VERSION 5.8 ;
BUSBITCHARS "[]" ;
DIVIDERCHAR "/" ;
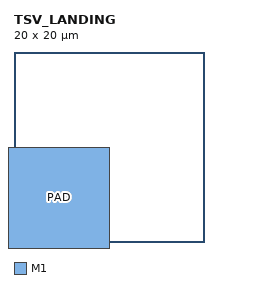
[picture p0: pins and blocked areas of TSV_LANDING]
MACRO TSV_LANDING
 CLASS COVER BUMP ;
 ORIGIN 0 0 ;
 SIZE 20 BY 20 ;
 PIN PAD
  DIRECTION INOUT ;
  USE SIGNAL ;
  PORT
   LAYER M1 ;
   RECT -10 -10 10 10 ;
  END
 END PAD
END TSV_LANDING
END LIBRARY
